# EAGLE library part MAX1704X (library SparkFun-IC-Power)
MAX17043/MAX17044: Battery Fuel Guage (43 is 1cell, 44 is 2cell)

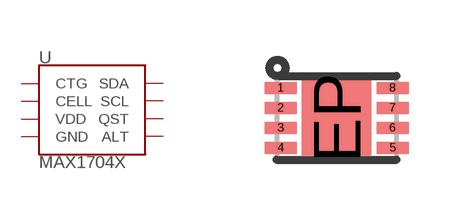
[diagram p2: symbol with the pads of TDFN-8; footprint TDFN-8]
Designator prefix U

## MAX1704X (PROD_ID: IC-10399)  [TDFN-8]
1  CTG
2  CELL
3  VDD
4  GND
5  ALT
6  QST
7  SCL
8  SDA
EP  GND

## Footprint TDFN-8 (pad centres in mm)
TDFN - 8pin, 2mmx3mm
smd 0.8 x 0.3: 1 -1.4,0.75; 2 -1.4,0.25; 3 -1.4,-0.25; 4 -1.4,-0.75; 5 1.4,-0.75; 6 1.4,-0.25; 7 1.4,0.25; 8 1.4,0.75
smd 1.73 x 1.88: EP 0,0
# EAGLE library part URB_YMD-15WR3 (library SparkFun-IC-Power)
MORNSUN DC/DC Converter URB_YMD-15WR3 URB2405YMD-15WR3: Input 24V (9V-36V), Output 5.0V 3.0A

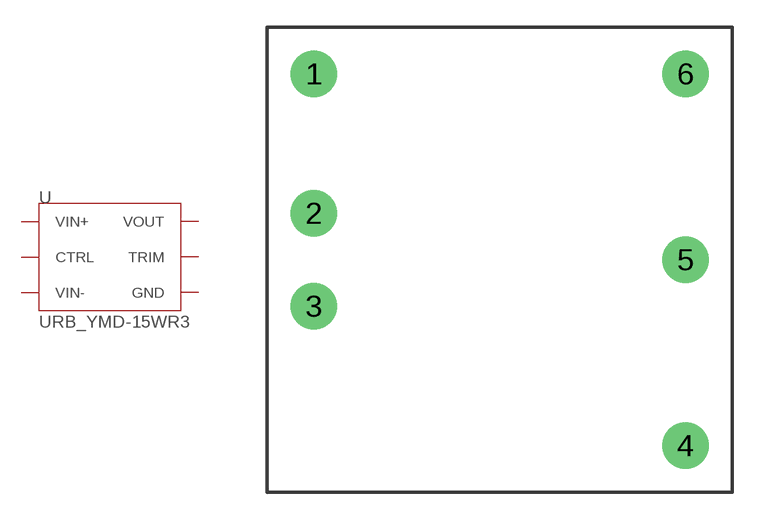
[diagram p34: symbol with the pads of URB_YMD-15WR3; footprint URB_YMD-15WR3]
Designator prefix -

## URB_YMD-15WR3__URB2405YMD-15WR3 (PROD_ID: COMP-19263; VALUE: URB2405YMD)  [URB_YMD-15WR3]
1  CTRL  in
2  VIN-  pwr
3  VIN+  pwr
4  VOUT  pwr
5  TRIM  in
6  GND  pwr

## Footprint URB_YMD-15WR3 (pad centres in mm)
MORNSUN DC/DC Converter URB_YMD-15WR3
drill 1.499 pad 2.54: 1 -10.16,10.16; 2 -10.16,2.54; 3 -10.16,-2.54; 4 10.16,-10.16; 5 10.16,0; 6 10.16,10.16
